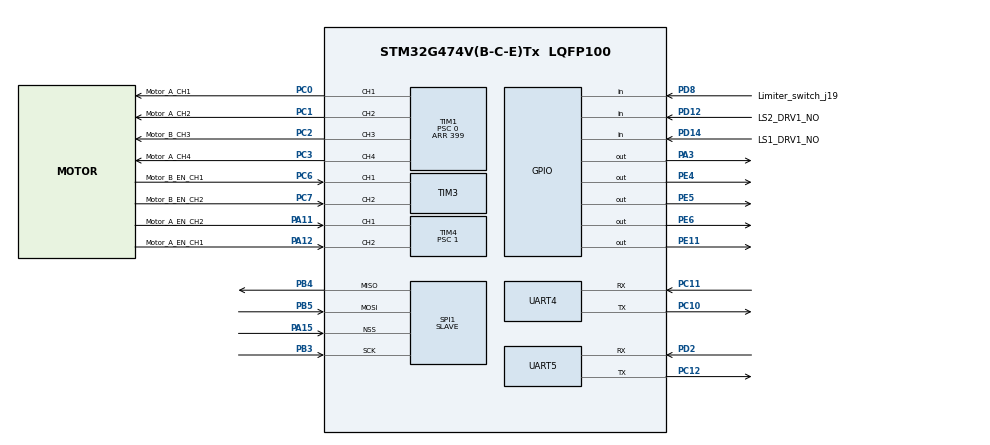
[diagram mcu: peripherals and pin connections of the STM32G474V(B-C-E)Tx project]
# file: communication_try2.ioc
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Mcu.Family=STM32G4
Mcu.Name=STM32G474V(B-C-E)Tx
Mcu.Package=LQFP100
NVIC.PriorityGroup=NVIC_PRIORITYGROUP_4
NVIC.TIM4_IRQn=true\:0\:0\:false\:false\:true\:true\:true\:true
NVIC.UART4_IRQn=true\:0\:0\:false\:false\:true\:true\:true\:true
NVIC.UART5_IRQn=true\:0\:0\:false\:false\:true\:true\:true\:true
PA11.GPIO_Label=Motor_A_EN_CH2
PA11.Signal=S_TIM4_CH1
PA12.GPIO_Label=Motor_A_EN_CH1
PA12.Signal=S_TIM4_CH2
PA15.GPIO_Speed=GPIO_SPEED_FREQ_VERY_HIGH
PA15.Mode=NSS_Signal_Hard_Input
PA15.Signal=SPI1_NSS
PA3.PinState=GPIO_PIN_SET
PA3.Signal=GPIO_Output
PB3.GPIO_Speed=GPIO_SPEED_FREQ_VERY_HIGH
PB3.Mode=Full_Duplex_Slave
PB3.Signal=SPI1_SCK
PB4.GPIO_Speed=GPIO_SPEED_FREQ_VERY_HIGH
PB4.Mode=Full_Duplex_Slave
PB4.Signal=SPI1_MISO
PB5.GPIO_Speed=GPIO_SPEED_FREQ_VERY_HIGH
PB5.Mode=Full_Duplex_Slave
PB5.Signal=SPI1_MOSI
PC0.GPIO_Label=Motor_A_CH1
PC0.Signal=S_TIM1_CH1
PC1.GPIO_Label=Motor_A_CH2
PC1.Signal=S_TIM1_CH2
PC10.Mode=Asynchronous
PC10.Signal=UART4_TX
PC11.Mode=Asynchronous
PC11.Signal=UART4_RX
PC12.Mode=Asynchronous
PC12.Signal=UART5_TX
PC2.GPIO_Label=Motor_B_CH3
PC2.Signal=S_TIM1_CH3
PC3.GPIO_Label=Motor_A_CH4
PC3.Signal=S_TIM1_CH4
PC6.GPIO_Label=Motor_B_EN_CH1
PC6.Signal=S_TIM3_CH1
PC7.GPIO_Label=Motor_B_EN_CH2
PC7.Signal=S_TIM3_CH2
PD12.GPIO_Label=LS2_DRV1_NO
PD12.Signal=GPIO_Input
PD14.GPIO_Label=LS1_DRV1_NO
PD14.Signal=GPIO_Input
PD2.Mode=Asynchronous
PD2.Signal=UART5_RX
PD8.GPIO_Label=Limiter_switch_j19
PD8.Signal=GPIO_Input
PE11.PinState=GPIO_PIN_SET
PE11.Signal=GPIO_Output
PE4.Signal=GPIO_Output
PE5.Signal=GPIO_Output
PE6.Signal=GPIO_Output
PF0-OSC_IN.Mode=HSE-External-Oscillator
PF0-OSC_IN.Signal=RCC_OSC_IN
PF1-OSC_OUT.Mode=HSE-External-Oscillator
PF1-OSC_OUT.Signal=RCC_OSC_OUT
ProjectManager.HeapSize=0x200
ProjectManager.StackSize=0x400
ProjectManager.TargetToolchain=STM32CubeIDE
RCC.ADC12Freq_Value=64000000
RCC.ADC345Freq_Value=64000000
RCC.AHBCLKDivider=RCC_SYSCLK_DIV4
RCC.AHBFreq_Value=16000000
RCC.APB1Freq_Value=16000000
RCC.APB1TimFreq_Value=16000000
RCC.APB2Freq_Value=16000000
RCC.APB2TimFreq_Value=16000000
RCC.CortexFreq_Value=16000000
RCC.EXTERNAL_CLOCK_VALUE=12288000
RCC.HCLKFreq_Value=16000000
RCC.HSE_VALUE=24000000
RCC.HSI48_VALUE=48000000
RCC.HSI_VALUE=16000000
RCC.LSE_VALUE=32768
RCC.SYSCLKFreq_VALUE=64000000
RCC.SYSCLKSource=RCC_SYSCLKSOURCE_PLLCLK
RCC.USBFreq_Value=64000000
RCC.VCOOutputFreq_Value=128000000
SH.S_TIM1_CH1.0=TIM1_CH1,PWM Generation1 CH1
SH.S_TIM1_CH2.0=TIM1_CH2,PWM Generation2 CH2
SH.S_TIM1_CH3.0=TIM1_CH3,PWM Generation3 CH3
SH.S_TIM1_CH4.0=TIM1_CH4,PWM Generation4 CH4
SH.S_TIM3_CH1.0=TIM3_CH1,Encoder_Interface
SH.S_TIM3_CH2.0=TIM3_CH2,Encoder_Interface
SH.S_TIM4_CH1.0=TIM4_CH1,Encoder_Interface
SH.S_TIM4_CH2.0=TIM4_CH2,Encoder_Interface
SPI1.DataSize=SPI_DATASIZE_8BIT
SPI1.Direction=SPI_DIRECTION_2LINES
SPI1.Mode=SPI_MODE_SLAVE
SPI1.VirtualNSS=VM_NSSHARD
SPI1.VirtualType=VM_SLAVE
TIM1.Channel-PWM\ Generation1\ CH1=TIM_CHANNEL_1
TIM1.Channel-PWM\ Generation2\ CH2=TIM_CHANNEL_2
TIM1.Channel-PWM\ Generation3\ CH3=TIM_CHANNEL_3
TIM1.Channel-PWM\ Generation4\ CH4=TIM_CHANNEL_4
TIM1.PeriodNoDither=399
TIM1.Prescaler=0
TIM3.EncoderMode=TIM_ENCODERMODE_TI12
TIM4.AutoReloadPreload=TIM_AUTORELOAD_PRELOAD_ENABLE
TIM4.EncoderMode=TIM_ENCODERMODE_TI12
TIM4.IC1Filter=1
TIM4.IC1Polarity=TIM_ICPOLARITY_RISING
TIM4.IC2Filter=1
TIM4.Prescaler=1
VP_SYS_VS_DBSignals.Mode=DisableDeadBatterySignals
VP_TIM1_VS_ClockSourceINT.Mode=Internal
board=custom

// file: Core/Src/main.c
/* USER CODE BEGIN Header */
/**
  ******************************************************************************
  * @file           : main.c
  * @brief          : Main program body
  ******************************************************************************
  * @attention
  *
  * Copyright (c) 2024 STMicroelectronics.
  * All rights reserved.
  *
  * This software is licensed under terms that can be found in the LICENSE file
  * in the root directory of this software component.
  * If no LICENSE file comes with this software, it is provided AS-IS.
  *
  ******************************************************************************
  */
/* USER CODE END Header */
#include "main.h"

/* USER CODE BEGIN Includes */
#include "call_center.h"
#include <stdint.h>
#include <string.h>
#include <stdlib.h>
#include <stdio.h>

/* USER CODE END Includes */

SPI_HandleTypeDef hspi1;

TIM_HandleTypeDef htim1;
TIM_HandleTypeDef htim3;
TIM_HandleTypeDef htim4;

UART_HandleTypeDef huart4;
UART_HandleTypeDef huart5;

void SystemClock_Config(void);
static void MX_GPIO_Init(void);
static void MX_SPI1_Init(void);
static void MX_UART5_Init(void);
static void MX_UART4_Init(void);
static void MX_TIM1_Init(void);
static void MX_TIM3_Init(void);
static void MX_TIM4_Init(void);

int main(void)
{

  /* MCU Configuration--------------------------------------------------------*/

  /* Reset of all peripherals, Initializes the Flash interface and the Systick. */
  HAL_Init();

  /* Configure the system clock */
  SystemClock_Config();

  /* Initialize all configured peripherals */
  MX_GPIO_Init();
  MX_SPI1_Init();
  MX_UART5_Init();
  MX_UART4_Init();
  MX_TIM1_Init();
  MX_TIM3_Init();
  MX_TIM4_Init();

  /* Infinite loop */
  /* USER CODE BEGIN WHILE */
  while (1)
  {

	  SPI_Communication();
    /* USER CODE END WHILE */

  }
}

void SystemClock_Config(void)
{
  RCC_OscInitTypeDef RCC_OscInitStruct = {0};
  RCC_ClkInitTypeDef RCC_ClkInitStruct = {0};

  /** Configure the main internal regulator output voltage
  */
  HAL_PWREx_ControlVoltageScaling(PWR_REGULATOR_VOLTAGE_SCALE1);

  /** Initializes the RCC Oscillators according to the specified parameters
  * in the RCC_OscInitTypeDef structure.
  */
  RCC_OscInitStruct.OscillatorType = RCC_OSCILLATORTYPE_HSI;
  RCC_OscInitStruct.HSIState = RCC_HSI_ON;
  RCC_OscInitStruct.HSICalibrationValue = RCC_HSICALIBRATION_DEFAULT;
  RCC_OscInitStruct.PLL.PLLState = RCC_PLL_ON;
  RCC_OscInitStruct.PLL.PLLSource = RCC_PLLSOURCE_HSI;
  RCC_OscInitStruct.PLL.PLLM = RCC_PLLM_DIV1;
  RCC_OscInitStruct.PLL.PLLN = 8;
  RCC_OscInitStruct.PLL.PLLP = RCC_PLLP_DIV2;
  RCC_OscInitStruct.PLL.PLLQ = RCC_PLLQ_DIV2;
  RCC_OscInitStruct.PLL.PLLR = RCC_PLLR_DIV2;
  if (HAL_RCC_OscConfig(&RCC_OscInitStruct) != HAL_OK)
  {
    Error_Handler();
  }

  /** Initializes the CPU, AHB and APB buses clocks
  */
  RCC_ClkInitStruct.ClockType = RCC_CLOCKTYPE_HCLK|RCC_CLOCKTYPE_SYSCLK
                              |RCC_CLOCKTYPE_PCLK1|RCC_CLOCKTYPE_PCLK2;
  RCC_ClkInitStruct.SYSCLKSource = RCC_SYSCLKSOURCE_PLLCLK;
  RCC_ClkInitStruct.AHBCLKDivider = RCC_SYSCLK_DIV2;
  RCC_ClkInitStruct.APB1CLKDivider = RCC_HCLK_DIV1;
  RCC_ClkInitStruct.APB2CLKDivider = RCC_HCLK_DIV1;

  if (HAL_RCC_ClockConfig(&RCC_ClkInitStruct, FLASH_LATENCY_1) != HAL_OK)
  {
    Error_Handler();
  }
}

static void MX_SPI1_Init(void)
{

  /* SPI1 parameter configuration*/
  hspi1.Instance = SPI1;
  hspi1.Init.Mode = SPI_MODE_SLAVE;
  hspi1.Init.Direction = SPI_DIRECTION_2LINES;
  hspi1.Init.DataSize = SPI_DATASIZE_8BIT;
  hspi1.Init.CLKPolarity = SPI_POLARITY_LOW;
  hspi1.Init.CLKPhase = SPI_PHASE_1EDGE;
  hspi1.Init.NSS = SPI_NSS_HARD_INPUT;
  hspi1.Init.FirstBit = SPI_FIRSTBIT_MSB;
  hspi1.Init.TIMode = SPI_TIMODE_DISABLE;
  hspi1.Init.CRCCalculation = SPI_CRCCALCULATION_DISABLE;
  hspi1.Init.CRCPolynomial = 7;
  hspi1.Init.CRCLength = SPI_CRC_LENGTH_DATASIZE;
  hspi1.Init.NSSPMode = SPI_NSS_PULSE_DISABLE;
  if (HAL_SPI_Init(&hspi1) != HAL_OK)
  {
    Error_Handler();
  }

}

static void MX_TIM1_Init(void)
{

  TIM_ClockConfigTypeDef sClockSourceConfig = {0};
  TIM_MasterConfigTypeDef sMasterConfig = {0};
  TIM_OC_InitTypeDef sConfigOC = {0};
  TIM_BreakDeadTimeConfigTypeDef sBreakDeadTimeConfig = {0};

  htim1.Instance = TIM1;
  htim1.Init.Prescaler = 0;
  htim1.Init.CounterMode = TIM_COUNTERMODE_UP;
  htim1.Init.Period = 399;
  htim1.Init.ClockDivision = TIM_CLOCKDIVISION_DIV1;
  htim1.Init.RepetitionCounter = 0;
  htim1.Init.AutoReloadPreload = TIM_AUTORELOAD_PRELOAD_DISABLE;
  if (HAL_TIM_Base_Init(&htim1) != HAL_OK)
  {
    Error_Handler();
  }
  sClockSourceConfig.ClockSource = TIM_CLOCKSOURCE_INTERNAL;
  if (HAL_TIM_ConfigClockSource(&htim1, &sClockSourceConfig) != HAL_OK)
  {
    Error_Handler();
  }
  if (HAL_TIM_PWM_Init(&htim1) != HAL_OK)
  {
    Error_Handler();
  }
  sMasterConfig.MasterOutputTrigger = TIM_TRGO_RESET;
  sMasterConfig.MasterOutputTrigger2 = TIM_TRGO2_RESET;
  sMasterConfig.MasterSlaveMode = TIM_MASTERSLAVEMODE_DISABLE;
  if (HAL_TIMEx_MasterConfigSynchronization(&htim1, &sMasterConfig) != HAL_OK)
  {
    Error_Handler();
  }
  sConfigOC.OCMode = TIM_OCMODE_PWM1;
  sConfigOC.Pulse = 0;
  sConfigOC.OCPolarity = TIM_OCPOLARITY_HIGH;
  sConfigOC.OCNPolarity = TIM_OCNPOLARITY_HIGH;
  sConfigOC.OCFastMode = TIM_OCFAST_DISABLE;
  sConfigOC.OCIdleState = TIM_OCIDLESTATE_RESET;
  sConfigOC.OCNIdleState = TIM_OCNIDLESTATE_RESET;
  if (HAL_TIM_PWM_ConfigChannel(&htim1, &sConfigOC, TIM_CHANNEL_1) != HAL_OK)
  {
    Error_Handler();
  }
  if (HAL_TIM_PWM_ConfigChannel(&htim1, &sConfigOC, TIM_CHANNEL_2) != HAL_OK)
  {
    Error_Handler();
  }
  if (HAL_TIM_PWM_ConfigChannel(&htim1, &sConfigOC, TIM_CHANNEL_3) != HAL_OK)
  {
    Error_Handler();
  }
  if (HAL_TIM_PWM_ConfigChannel(&htim1, &sConfigOC, TIM_CHANNEL_4) != HAL_OK)
  {
    Error_Handler();
  }
  sBreakDeadTimeConfig.OffStateRunMode = TIM_OSSR_DISABLE;
  sBreakDeadTimeConfig.OffStateIDLEMode = TIM_OSSI_DISABLE;
  sBreakDeadTimeConfig.LockLevel = TIM_LOCKLEVEL_OFF;
  sBreakDeadTimeConfig.DeadTime = 0;
  sBreakDeadTimeConfig.BreakState = TIM_BREAK_DISABLE;
  sBreakDeadTimeConfig.BreakPolarity = TIM_BREAKPOLARITY_HIGH;
  sBreakDeadTimeConfig.BreakFilter = 0;
  sBreakDeadTimeConfig.BreakAFMode = TIM_BREAK_AFMODE_INPUT;
  sBreakDeadTimeConfig.Break2State = TIM_BREAK2_DISABLE;
  sBreakDeadTimeConfig.Break2Polarity = TIM_BREAK2POLARITY_HIGH;
  sBreakDeadTimeConfig.Break2Filter = 0;
  sBreakDeadTimeConfig.Break2AFMode = TIM_BREAK_AFMODE_INPUT;
  sBreakDeadTimeConfig.AutomaticOutput = TIM_AUTOMATICOUTPUT_DISABLE;
  if (HAL_TIMEx_ConfigBreakDeadTime(&htim1, &sBreakDeadTimeConfig) != HAL_OK)
  {
    Error_Handler();
  }
  HAL_TIM_MspPostInit(&htim1);

}

static void MX_TIM3_Init(void)
{

  TIM_Encoder_InitTypeDef sConfig = {0};
  TIM_MasterConfigTypeDef sMasterConfig = {0};

  htim3.Instance = TIM3;
  htim3.Init.Prescaler = 0;
  htim3.Init.CounterMode = TIM_COUNTERMODE_UP;
  htim3.Init.Period = 65535;
  htim3.Init.ClockDivision = TIM_CLOCKDIVISION_DIV1;
  htim3.Init.AutoReloadPreload = TIM_AUTORELOAD_PRELOAD_DISABLE;
  sConfig.EncoderMode = TIM_ENCODERMODE_TI12;
  sConfig.IC1Polarity = TIM_ICPOLARITY_RISING;
  sConfig.IC1Selection = TIM_ICSELECTION_DIRECTTI;
  sConfig.IC1Prescaler = TIM_ICPSC_DIV1;
  sConfig.IC1Filter = 0;
  sConfig.IC2Polarity = TIM_ICPOLARITY_RISING;
  sConfig.IC2Selection = TIM_ICSELECTION_DIRECTTI;
  sConfig.IC2Prescaler = TIM_ICPSC_DIV1;
  sConfig.IC2Filter = 0;
  if (HAL_TIM_Encoder_Init(&htim3, &sConfig) != HAL_OK)
  {
    Error_Handler();
  }
  sMasterConfig.MasterOutputTrigger = TIM_TRGO_RESET;
  sMasterConfig.MasterSlaveMode = TIM_MASTERSLAVEMODE_DISABLE;
  if (HAL_TIMEx_MasterConfigSynchronization(&htim3, &sMasterConfig) != HAL_OK)
  {
    Error_Handler();
  }

}

static void MX_TIM4_Init(void)
{

  TIM_Encoder_InitTypeDef sConfig = {0};
  TIM_MasterConfigTypeDef sMasterConfig = {0};

  htim4.Instance = TIM4;
  htim4.Init.Prescaler = 1;
  htim4.Init.CounterMode = TIM_COUNTERMODE_UP;
  htim4.Init.Period = 65535;
  htim4.Init.ClockDivision = TIM_CLOCKDIVISION_DIV1;
  htim4.Init.AutoReloadPreload = TIM_AUTORELOAD_PRELOAD_ENABLE;
  sConfig.EncoderMode = TIM_ENCODERMODE_TI12;
  sConfig.IC1Polarity = TIM_ICPOLARITY_RISING;
  sConfig.IC1Selection = TIM_ICSELECTION_DIRECTTI;
  sConfig.IC1Prescaler = TIM_ICPSC_DIV1;
  sConfig.IC1Filter = 1;
  sConfig.IC2Polarity = TIM_ICPOLARITY_RISING;
  sConfig.IC2Selection = TIM_ICSELECTION_DIRECTTI;
  sConfig.IC2Prescaler = TIM_ICPSC_DIV1;
  sConfig.IC2Filter = 1;
  if (HAL_TIM_Encoder_Init(&htim4, &sConfig) != HAL_OK)
  {
    Error_Handler();
  }
  sMasterConfig.MasterOutputTrigger = TIM_TRGO_RESET;
  sMasterConfig.MasterSlaveMode = TIM_MASTERSLAVEMODE_DISABLE;
  if (HAL_TIMEx_MasterConfigSynchronization(&htim4, &sMasterConfig) != HAL_OK)
  {
    Error_Handler();
  }

}

static void MX_UART4_Init(void)
{

  huart4.Instance = UART4;
  huart4.Init.BaudRate = 115200;
  huart4.Init.WordLength = UART_WORDLENGTH_8B;
  huart4.Init.StopBits = UART_STOPBITS_1;
  huart4.Init.Parity = UART_PARITY_NONE;
  huart4.Init.Mode = UART_MODE_TX_RX;
  huart4.Init.HwFlowCtl = UART_HWCONTROL_NONE;
  huart4.Init.OverSampling = UART_OVERSAMPLING_16;
  huart4.Init.OneBitSampling = UART_ONE_BIT_SAMPLE_DISABLE;
  huart4.Init.ClockPrescaler = UART_PRESCALER_DIV1;
  huart4.AdvancedInit.AdvFeatureInit = UART_ADVFEATURE_NO_INIT;
  if (HAL_UART_Init(&huart4) != HAL_OK)
  {
    Error_Handler();
  }
  if (HAL_UARTEx_SetTxFifoThreshold(&huart4, UART_TXFIFO_THRESHOLD_1_8) != HAL_OK)
  {
    Error_Handler();
  }
  if (HAL_UARTEx_SetRxFifoThreshold(&huart4, UART_RXFIFO_THRESHOLD_1_8) != HAL_OK)
  {
    Error_Handler();
  }
  if (HAL_UARTEx_DisableFifoMode(&huart4) != HAL_OK)
  {
    Error_Handler();
  }

}

static void MX_UART5_Init(void)
{

  huart5.Instance = UART5;
  huart5.Init.BaudRate = 115200;
  huart5.Init.WordLength = UART_WORDLENGTH_8B;
  huart5.Init.StopBits = UART_STOPBITS_1;
  huart5.Init.Parity = UART_PARITY_NONE;
  huart5.Init.Mode = UART_MODE_TX_RX;
  huart5.Init.HwFlowCtl = UART_HWCONTROL_NONE;
  huart5.Init.OverSampling = UART_OVERSAMPLING_16;
  huart5.Init.OneBitSampling = UART_ONE_BIT_SAMPLE_DISABLE;
  huart5.Init.ClockPrescaler = UART_PRESCALER_DIV1;
  huart5.AdvancedInit.AdvFeatureInit = UART_ADVFEATURE_NO_INIT;
  if (HAL_UART_Init(&huart5) != HAL_OK)
  {
    Error_Handler();
  }
  if (HAL_UARTEx_SetTxFifoThreshold(&huart5, UART_TXFIFO_THRESHOLD_1_8) != HAL_OK)
  {
    Error_Handler();
  }
  if (HAL_UARTEx_SetRxFifoThreshold(&huart5, UART_RXFIFO_THRESHOLD_1_8) != HAL_OK)
  {
    Error_Handler();
  }
  if (HAL_UARTEx_DisableFifoMode(&huart5) != HAL_OK)
  {
    Error_Handler();
  }

}

static void MX_GPIO_Init(void)
{
  GPIO_InitTypeDef GPIO_InitStruct = {0};

  /* GPIO Ports Clock Enable */
  __HAL_RCC_GPIOE_CLK_ENABLE();
  __HAL_RCC_GPIOF_CLK_ENABLE();
  __HAL_RCC_GPIOC_CLK_ENABLE();
  __HAL_RCC_GPIOA_CLK_ENABLE();
  __HAL_RCC_GPIOD_CLK_ENABLE();
  __HAL_RCC_GPIOB_CLK_ENABLE();

  /*Configure GPIO pin Output Level */
  HAL_GPIO_WritePin(GPIOA, GPIO_PIN_3, GPIO_PIN_SET);

  /*Configure GPIO pin Output Level */
  HAL_GPIO_WritePin(GPIOE, GPIO_PIN_11, GPIO_PIN_SET);

  /*Configure GPIO pins : PE2 PE3 PE4 PE5
                           PE6 PE7 PE0 PE1 */
  GPIO_InitStruct.Pin = GPIO_PIN_2|GPIO_PIN_3|GPIO_PIN_4|GPIO_PIN_5
                          |GPIO_PIN_6|GPIO_PIN_7|GPIO_PIN_0|GPIO_PIN_1;
  GPIO_InitStruct.Mode = GPIO_MODE_INPUT;
  GPIO_InitStruct.Pull = GPIO_NOPULL;
  HAL_GPIO_Init(GPIOE, &GPIO_InitStruct);

  /*Configure GPIO pin : PA3 */
  GPIO_InitStruct.Pin = GPIO_PIN_3;
  GPIO_InitStruct.Mode = GPIO_MODE_OUTPUT_PP;
  GPIO_InitStruct.Pull = GPIO_NOPULL;
  GPIO_InitStruct.Speed = GPIO_SPEED_FREQ_LOW;
  HAL_GPIO_Init(GPIOA, &GPIO_InitStruct);

  /*Configure GPIO pin : PE11 */
  GPIO_InitStruct.Pin = GPIO_PIN_11;
  GPIO_InitStruct.Mode = GPIO_MODE_OUTPUT_PP;
  GPIO_InitStruct.Pull = GPIO_NOPULL;
  GPIO_InitStruct.Speed = GPIO_SPEED_FREQ_LOW;
  HAL_GPIO_Init(GPIOE, &GPIO_InitStruct);

  /*Configure GPIO pins : Limiter_switch_j19_Pin LS2_DRV1_NO_Pin LS1_DRV1_NO_Pin */
  GPIO_InitStruct.Pin = Limiter_switch_j19_Pin|LS2_DRV1_NO_Pin|LS1_DRV1_NO_Pin;
  GPIO_InitStruct.Mode = GPIO_MODE_INPUT;
  GPIO_InitStruct.Pull = GPIO_NOPULL;
  HAL_GPIO_Init(GPIOD, &GPIO_InitStruct);

}

void Error_Handler(void)
{
  __disable_irq();
  while (1)
  {
  }
}
